VERSION 5.7 ;
  NOWIREEXTENSIONATPIN ON ;
  DIVIDERCHAR "/" ;
  BUSBITCHARS "[]" ;
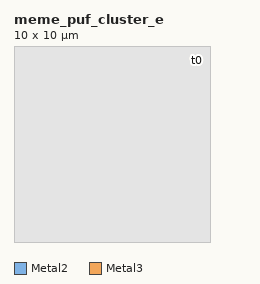
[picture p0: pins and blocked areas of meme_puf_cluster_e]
MACRO meme_puf_cluster_e
  CLASS BLOCK ;
  FOREIGN meme_puf_cluster_e ;
  ORIGIN 0.000 0.000 ;
  SIZE 10.000 BY 10.000 ;
  PIN HI
    DIRECTION INOUT ;
    USE ANALOG ;
    PORT
      LAYER Metal2 ;
        RECT 80.100 12.300 80.600 16.300 ;
    END
  END HI
  PIN LO
    DIRECTION INOUT ;
    USE ANALOG ;
    PORT
      LAYER Metal2 ;
        RECT 80.100 17.300 80.600 21.300 ;
    END
  END LO
  PIN t0
    DIRECTION INOUT ;
    USE ANALOG ;
    PORT
      LAYER Metal3 ;
        RECT 80.100 23.100 80.600 23.700 ;
    END
  END t0
  PIN t1
    DIRECTION INOUT ;
    USE ANALOG ;
    PORT
      LAYER Metal3 ;
        RECT 80.100 24.200 80.600 24.800 ;
    END
  END t1
  PIN t2
    DIRECTION INOUT ;
    USE ANALOG ;
    PORT
      LAYER Metal3 ;
        RECT 80.100 25.300 80.600 25.900 ;
    END
  END t2
  PIN t3
    DIRECTION INOUT ;
    USE ANALOG ;
    PORT
      LAYER Metal3 ;
        RECT 80.100 26.400 80.600 27.000 ;
    END
  END t3
  PIN t4
    DIRECTION INOUT ;
    USE ANALOG ;
    PORT
      LAYER Metal3 ;
        RECT 80.100 27.500 80.600 28.100 ;
    END
  END t4
  PIN t5
    DIRECTION INOUT ;
    USE ANALOG ;
    PORT
      LAYER Metal3 ;
        RECT 80.100 28.600 80.600 29.200 ;
    END
  END t5
  PIN t6
    DIRECTION INOUT ;
    USE ANALOG ;
    PORT
      LAYER Metal3 ;
        RECT 80.100 29.700 80.600 30.300 ;
    END
  END t6
  PIN t7
    DIRECTION INOUT ;
    USE ANALOG ;
    PORT
      LAYER Metal3 ;
        RECT 80.100 30.800 80.600 31.400 ;
    END
  END t7
  OBS
      LAYER Metal1 ;
        RECT 0.000 0.000 80.600 44.900 ;
      LAYER Metal2 ;
        RECT 0.000 0.000 80.600 44.900 ;
      LAYER Metal3 ;
        RECT 0.000 0.000 80.600 44.900 ;
  END
END meme_puf_cluster_e
END LIBRARY
